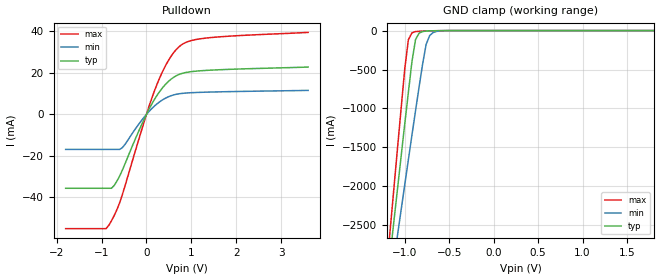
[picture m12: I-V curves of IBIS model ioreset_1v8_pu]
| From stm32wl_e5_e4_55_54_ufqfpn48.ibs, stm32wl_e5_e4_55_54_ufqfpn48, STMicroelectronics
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|   Model ioreset_1v8_pu
[Model]  ioreset_1v8_pu
Model_type I/O_open_drain
Polarity   Inverting
Enable   Active-High
Vinl =   0.540000V
Vinh =   1.260000V
Vmeas =  0.900000V
Cref =   100.000000nF
Rref =   1.000000k
Vref =   1.800000V
C_comp   0.473010pF   0.460860pF   0.564710pF
[Temperature Range]   25.000000   0.125000k   -40.000000
[Pullup Reference]   1.800000V   1.600000V   2.000000V
[Pulldown Reference]   0.0V   0.0V   0.0V
[POWER Clamp Reference]   1.800000V   1.600000V   2.000000V
[GND Clamp Reference]   0.0V   0.0V   0.0V
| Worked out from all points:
|   slope of the pulldown table from 0 to 0.27 V, typ, clamps not added: 26.4 ohm
|   GND clamp passes 1 mA (typ) near -0.60 V on its own axis
[Pulldown]
|Voltage   I(typ)   I(min)   I(max)
-1.8V     -35.64mA   -16.93mA   -55.1mA
-900mV    -35.64mA   -16.93mA   -55.1mA
-840mV    -35.64mA   -16.93mA   -53.52mA
-720mV    -34.31mA   -16.93mA   -48.86mA
-540mV    -27.04mA   -16.13mA   -38.89mA
-60mV     -2.742mA   -1.574mA   -4.207mA
240mV     9.303mA    5.14mA     14.78mA
480mV     15.67mA    8.374mA    25.64mA
720mV     19.18mA    9.883mA    32.46mA
960mV     20.46mA    10.37mA    35.32mA
1.32V     21.15mA    10.67mA    36.72mA
3.6V      22.78mA    11.53mA    39.48mA
[GND_clamp]
|Voltage   I(typ)   I(min)   I(max)
-1.8V     -9.477A    -8.509A    -9.704A
-1.2V     -3.243A    -3.574A    -3.012A
-1.16V    -2.83A     -3.252A    -2.501A
-1.12V    -2.418A    -2.932A    -1.991A
-1.08V    -2.008A    -2.612A    -1.484A
-1V       -1.194A    -1.975A    -486.6mA
-960mV    -792.8mA   -1.659A    -118.4mA
-920mV    -402mA     -1.345A    -29.21mA
-880mV    -117.9mA   -1.034A    -12.85mA
-760mV    -5.956mA   -176.1mA   -5.379mA
-680mV    -2.455mA   -23.94mA   -2.76mA
1.8V      0A         0A         0A
[POWER_clamp]
|Voltage   I(typ)   I(min)   I(max)
-1.8V     0A         0A         0A
0V        0A         0A         0A
[Ramp]
| variable   typ   min   max
dV/dt_r  1.07940/0.30684u   0.95900/0.30028u   1.19957/0.30024u
dV/dt_f  1.07940/13.44459n   0.95900/23.74701n   1.19957/9.53815n
R_load = 40.000000k
